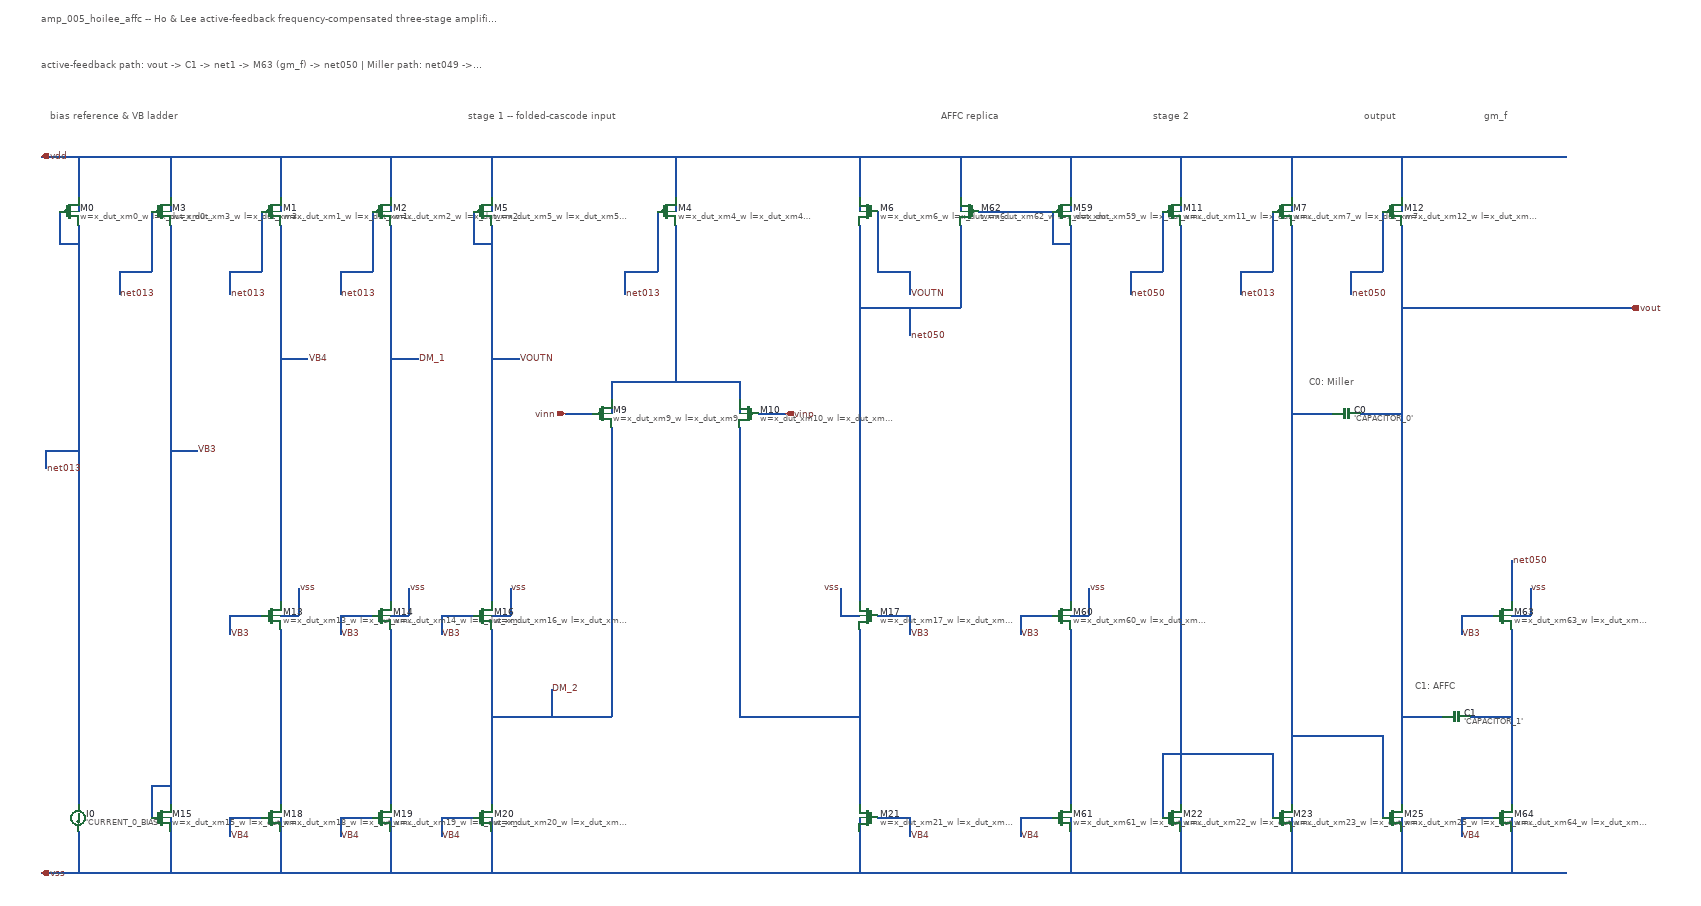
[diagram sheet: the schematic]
v {xschem version=3.4.6 file_version=1.2
}
G {}
K {}
V {}
S {}
E {}
T {amp_005_hoilee_affc   --   Ho \& Lee active-feedback frequency-compensated three-stage amplifier   (IHP SG13G2)} 140 -2090 0 0 0.6 0.6 {}
T {active-feedback path:   vout  ->  C1  ->  net1  ->  M63 (gm_f)  ->  net050      |     Miller path:   net049  ->  C0  ->  vout} 140 -1990 0 0 0.42 0.42 {}
T {bias reference \& VB ladder} 160 -1880 0 0 0.45 0.45 {}
T {stage 1  --  folded-cascode input} 1070 -1880 0 0 0.45 0.45 {}
T {AFFC replica} 2100 -1880 0 0 0.45 0.45 {}
T {stage 2} 2560 -1880 0 0 0.45 0.45 {}
T {output} 3020 -1880 0 0 0.45 0.45 {}
T {gm_f} 3280 -1880 0 0 0.45 0.45 {}
T {C0: Miller} 2900 -1300 0 0 0.4 0.4 {}
T {C1: AFFC} 3130 -640 0 0 0.4 0.4 {}
N 140 -1780 3460 -1780 {}
N 140 -220 3460 -220 {}
N 220 -1780 220 -1660 {}
N 420 -1780 420 -1660 {}
N 660 -1780 660 -1660 {}
N 900 -1780 900 -1660 {}
N 420 -340 420 -220 {}
N 660 -340 660 -220 {}
N 900 -340 900 -220 {}
N 1120 -1780 1120 -1660 {}
N 1120 -340 1120 -220 {}
N 1520 -1780 1520 -1660 {}
N 1920 -1780 1920 -1660 {}
N 1920 -340 1920 -220 {}
N 2140 -1780 2140 -1660 {}
N 2380 -1780 2380 -1660 {}
N 2380 -340 2380 -220 {}
N 2620 -1780 2620 -1660 {}
N 2620 -340 2620 -220 {}
N 2860 -1780 2860 -1660 {}
N 2860 -340 2860 -220 {}
N 3100 -1780 3100 -1660 {}
N 3100 -340 3100 -220 {}
N 3340 -340 3340 -220 {}
N 220 -310 220 -220 {}
N 180 -1660 180 -1590 {}
N 180 -1590 220 -1590 {}
N 220 -1630 220 -370 {}
N 150 -1140 220 -1140 {}
N 150 -1140 150 -1100 {}
N 380 -1660 380 -1530 {}
N 380 -1530 310 -1530 {}
N 310 -1530 310 -1480 {}
N 620 -1660 620 -1530 {}
N 620 -1530 550 -1530 {}
N 550 -1530 550 -1480 {}
N 860 -1660 860 -1530 {}
N 860 -1530 790 -1530 {}
N 790 -1530 790 -1480 {}
N 1480 -1660 1480 -1530 {}
N 1480 -1530 1410 -1530 {}
N 1410 -1530 1410 -1480 {}
N 2820 -1660 2820 -1530 {}
N 2820 -1530 2750 -1530 {}
N 2750 -1530 2750 -1480 {}
N 420 -1630 420 -370 {}
N 380 -340 380 -410 {}
N 380 -410 420 -410 {}
N 420 -1140 480 -1140 {}
N 620 -780 550 -780 {}
N 550 -780 550 -740 {}
N 860 -780 790 -780 {}
N 790 -780 790 -740 {}
N 1080 -780 1010 -780 {}
N 1010 -780 1010 -740 {}
N 1960 -780 2030 -780 {}
N 2030 -780 2030 -740 {}
N 2340 -780 2270 -780 {}
N 2270 -780 2270 -740 {}
N 3300 -780 3230 -780 {}
N 3230 -780 3230 -740 {}
N 660 -1630 660 -810 {}
N 660 -1340 720 -1340 {}
N 620 -340 550 -340 {}
N 550 -340 550 -300 {}
N 860 -340 790 -340 {}
N 790 -340 790 -300 {}
N 1080 -340 1010 -340 {}
N 1010 -340 1010 -300 {}
N 1960 -340 2030 -340 {}
N 2030 -340 2030 -300 {}
N 2340 -340 2270 -340 {}
N 2270 -340 2270 -300 {}
N 3300 -340 3230 -340 {}
N 3230 -340 3230 -300 {}
N 660 -750 660 -370 {}
N 900 -1630 900 -810 {}
N 900 -1340 960 -1340 {}
N 900 -750 900 -370 {}
N 660 -780 700 -780 {}
N 700 -780 700 -840 {}
N 900 -780 940 -780 {}
N 940 -780 940 -840 {}
N 1120 -1630 1120 -810 {}
N 1080 -1660 1080 -1590 {}
N 1080 -1590 1120 -1590 {}
N 1120 -1340 1180 -1340 {}
N 1960 -1660 1960 -1530 {}
N 1960 -1530 2030 -1530 {}
N 2030 -1530 2030 -1480 {}
N 1120 -780 1160 -780 {}
N 1160 -780 1160 -840 {}
N 1520 -1630 1520 -1290 {}
N 1380 -1290 1660 -1290 {}
N 1380 -1290 1380 -1220 {}
N 1660 -1290 1660 -1220 {}
N 1280 -1220 1340 -1220 {}
N 1700 -1220 1760 -1220 {}
N 1380 -1190 1380 -560 {}
N 1120 -560 1380 -560 {}
N 1120 -750 1120 -370 {}
N 1250 -560 1250 -620 {}
N 1660 -1190 1660 -560 {}
N 1660 -560 1920 -560 {}
N 1920 -750 1920 -370 {}
N 1920 -780 1880 -780 {}
N 1880 -780 1880 -840 {}
N 1920 -1630 1920 -810 {}
N 1920 -1450 2140 -1450 {}
N 2140 -1630 2140 -1450 {}
N 2030 -1450 2030 -1390 {}
N 2580 -1660 2580 -1530 {}
N 2580 -1530 2510 -1530 {}
N 2510 -1530 2510 -1480 {}
N 3060 -1660 3060 -1530 {}
N 3060 -1530 2990 -1530 {}
N 2990 -1530 2990 -1480 {}
N 3340 -810 3340 -900 {}
N 2380 -1630 2380 -810 {}
N 2340 -1660 2340 -1590 {}
N 2340 -1590 2380 -1590 {}
N 2180 -1660 2340 -1660 {}
N 2380 -750 2380 -370 {}
N 2380 -780 2420 -780 {}
N 2420 -780 2420 -840 {}
N 2620 -1630 2620 -370 {}
N 2580 -340 2580 -480 {}
N 2580 -480 2620 -480 {}
N 2820 -340 2820 -480 {}
N 2620 -480 2820 -480 {}
N 2860 -1630 2860 -370 {}
N 3060 -340 3060 -520 {}
N 2860 -520 3060 -520 {}
N 2860 -1220 2950 -1220 {}
N 3100 -1630 3100 -370 {}
N 3010 -1220 3100 -1220 {}
N 3100 -560 3190 -560 {}
N 3100 -1450 3600 -1450 {}
N 3250 -560 3340 -560 {}
N 3340 -750 3340 -370 {}
N 3340 -780 3380 -780 {}
N 3380 -780 3380 -840 {}
C {devices/sg13_lv_pmos_np.sym} 200 -1660 0 0 {name=M0 model=sg13_lv_pmos spiceprefix=X w=x_dut_xm0_w l=x_dut_xm0_l m=x_dut_xm0_m}
C {devices/sg13_lv_pmos_np.sym} 400 -1660 0 0 {name=M3 model=sg13_lv_pmos spiceprefix=X w=x_dut_xm3_w l=x_dut_xm3_l m=x_dut_xm3_m}
C {devices/sg13_lv_pmos_np.sym} 640 -1660 0 0 {name=M1 model=sg13_lv_pmos spiceprefix=X w=x_dut_xm1_w l=x_dut_xm1_l m=x_dut_xm1_m}
C {devices/sg13_lv_pmos_np.sym} 880 -1660 0 0 {name=M2 model=sg13_lv_pmos spiceprefix=X w=x_dut_xm2_w l=x_dut_xm2_l m=x_dut_xm2_m}
C {devices/sg13_lv_nmos_np.sym} 400 -340 0 0 {name=M15 model=sg13_lv_nmos spiceprefix=X w=x_dut_xm15_w l=x_dut_xm15_l m=x_dut_xm15_m}
C {devices/sg13_lv_nmos_np.sym} 640 -780 0 0 {name=M13 model=sg13_lv_nmos spiceprefix=X w=x_dut_xm13_w l=x_dut_xm13_l m=x_dut_xm13_m}
C {devices/sg13_lv_nmos_np.sym} 640 -340 0 0 {name=M18 model=sg13_lv_nmos spiceprefix=X w=x_dut_xm18_w l=x_dut_xm18_l m=x_dut_xm18_m}
C {devices/sg13_lv_nmos_np.sym} 880 -780 0 0 {name=M14 model=sg13_lv_nmos spiceprefix=X w=x_dut_xm14_w l=x_dut_xm14_l m=x_dut_xm14_m}
C {devices/sg13_lv_nmos_np.sym} 880 -340 0 0 {name=M19 model=sg13_lv_nmos spiceprefix=X w=x_dut_xm19_w l=x_dut_xm19_l m=x_dut_xm19_m}
C {devices/sg13_lv_pmos_np.sym} 1100 -1660 0 0 {name=M5 model=sg13_lv_pmos spiceprefix=X w=x_dut_xm5_w l=x_dut_xm5_l m=x_dut_xm5_m}
C {devices/sg13_lv_nmos_np.sym} 1100 -780 0 0 {name=M16 model=sg13_lv_nmos spiceprefix=X w=x_dut_xm16_w l=x_dut_xm16_l m=x_dut_xm16_m}
C {devices/sg13_lv_nmos_np.sym} 1100 -340 0 0 {name=M20 model=sg13_lv_nmos spiceprefix=X w=x_dut_xm20_w l=x_dut_xm20_l m=x_dut_xm20_m}
C {devices/sg13_lv_pmos_np.sym} 1360 -1220 0 0 {name=M9 model=sg13_lv_pmos spiceprefix=X w=x_dut_xm9_w l=x_dut_xm9_l m=x_dut_xm9_m}
C {devices/sg13_lv_pmos_np.sym} 1500 -1660 0 0 {name=M4 model=sg13_lv_pmos spiceprefix=X w=x_dut_xm4_w l=x_dut_xm4_l m=x_dut_xm4_m}
C {devices/sg13_lv_pmos_np.sym} 1680 -1220 0 1 {name=M10 model=sg13_lv_pmos spiceprefix=X w=x_dut_xm10_w l=x_dut_xm10_l m=x_dut_xm10_m}
C {devices/sg13_lv_pmos_np.sym} 1940 -1660 0 1 {name=M6 model=sg13_lv_pmos spiceprefix=X w=x_dut_xm6_w l=x_dut_xm6_l m=x_dut_xm6_m}
C {devices/sg13_lv_nmos_np.sym} 1940 -780 0 1 {name=M17 model=sg13_lv_nmos spiceprefix=X w=x_dut_xm17_w l=x_dut_xm17_l m=x_dut_xm17_m}
C {devices/sg13_lv_nmos_np.sym} 1940 -340 0 1 {name=M21 model=sg13_lv_nmos spiceprefix=X w=x_dut_xm21_w l=x_dut_xm21_l m=x_dut_xm21_m}
C {devices/sg13_lv_pmos_np.sym} 2160 -1660 0 1 {name=M62 model=sg13_lv_pmos spiceprefix=X w=x_dut_xm62_w l=x_dut_xm62_l m=x_dut_xm62_m}
C {devices/sg13_lv_pmos_np.sym} 2360 -1660 0 0 {name=M59 model=sg13_lv_pmos spiceprefix=X w=x_dut_xm59_w l=x_dut_xm59_l m=x_dut_xm59_m}
C {devices/sg13_lv_nmos_np.sym} 2360 -780 0 0 {name=M60 model=sg13_lv_nmos spiceprefix=X w=x_dut_xm60_w l=x_dut_xm60_l m=x_dut_xm60_m}
C {devices/sg13_lv_nmos_np.sym} 2360 -340 0 0 {name=M61 model=sg13_lv_nmos spiceprefix=X w=x_dut_xm61_w l=x_dut_xm61_l m=x_dut_xm61_m}
C {devices/sg13_lv_pmos_np.sym} 2600 -1660 0 0 {name=M11 model=sg13_lv_pmos spiceprefix=X w=x_dut_xm11_w l=x_dut_xm11_l m=x_dut_xm11_m}
C {devices/sg13_lv_nmos_np.sym} 2600 -340 0 0 {name=M22 model=sg13_lv_nmos spiceprefix=X w=x_dut_xm22_w l=x_dut_xm22_l m=x_dut_xm22_m}
C {devices/sg13_lv_pmos_np.sym} 2840 -1660 0 0 {name=M7 model=sg13_lv_pmos spiceprefix=X w=x_dut_xm7_w l=x_dut_xm7_l m=x_dut_xm7_m}
C {devices/sg13_lv_nmos_np.sym} 2840 -340 0 0 {name=M23 model=sg13_lv_nmos spiceprefix=X w=x_dut_xm23_w l=x_dut_xm23_l m=x_dut_xm23_m}
C {devices/sg13_lv_pmos_np.sym} 3080 -1660 0 0 {name=M12 model=sg13_lv_pmos spiceprefix=X w=x_dut_xm12_w l=x_dut_xm12_l m=x_dut_xm12_m}
C {devices/sg13_lv_nmos_np.sym} 3080 -340 0 0 {name=M25 model=sg13_lv_nmos spiceprefix=X w=x_dut_xm25_w l=x_dut_xm25_l m=x_dut_xm25_m}
C {devices/sg13_lv_nmos_np.sym} 3320 -780 0 0 {name=M63 model=sg13_lv_nmos spiceprefix=X w=x_dut_xm63_w l=x_dut_xm63_l m=x_dut_xm63_m}
C {devices/sg13_lv_nmos_np.sym} 3320 -340 0 0 {name=M64 model=sg13_lv_nmos spiceprefix=X w=x_dut_xm64_w l=x_dut_xm64_l m=x_dut_xm64_m}
C {devices/isource_np.sym} 220 -340 0 0 {name=I0 value='CURRENT_0_BIAS'}
C {devices/capa_np.sym} 2980 -1220 3 0 {name=C0 value='CAPACITOR_0'}
C {devices/capa_np.sym} 3220 -560 3 0 {name=C1 value='CAPACITOR_1'}
C {devices/iopin.sym} 140 -1780 0 1 {name=p0 lab=vdd}
C {devices/iopin.sym} 140 -220 0 1 {name=p1 lab=vss}
C {devices/lab_pin.sym} 150 -1100 0 1 {name=l2 sig_type=std_logic lab=net013}
C {devices/lab_pin.sym} 310 -1480 0 1 {name=l3 sig_type=std_logic lab=net013}
C {devices/lab_pin.sym} 550 -1480 0 1 {name=l4 sig_type=std_logic lab=net013}
C {devices/lab_pin.sym} 790 -1480 0 1 {name=l5 sig_type=std_logic lab=net013}
C {devices/lab_pin.sym} 1410 -1480 0 1 {name=l6 sig_type=std_logic lab=net013}
C {devices/lab_pin.sym} 2750 -1480 0 1 {name=l7 sig_type=std_logic lab=net013}
C {devices/lab_pin.sym} 480 -1140 0 1 {name=l8 sig_type=std_logic lab=VB3}
C {devices/lab_pin.sym} 550 -740 0 1 {name=l9 sig_type=std_logic lab=VB3}
C {devices/lab_pin.sym} 790 -740 0 1 {name=l10 sig_type=std_logic lab=VB3}
C {devices/lab_pin.sym} 1010 -740 0 1 {name=l11 sig_type=std_logic lab=VB3}
C {devices/lab_pin.sym} 2030 -740 0 1 {name=l12 sig_type=std_logic lab=VB3}
C {devices/lab_pin.sym} 2270 -740 0 1 {name=l13 sig_type=std_logic lab=VB3}
C {devices/lab_pin.sym} 3230 -740 0 1 {name=l14 sig_type=std_logic lab=VB3}
C {devices/lab_pin.sym} 720 -1340 0 1 {name=l15 sig_type=std_logic lab=VB4}
C {devices/lab_pin.sym} 550 -300 0 1 {name=l16 sig_type=std_logic lab=VB4}
C {devices/lab_pin.sym} 790 -300 0 1 {name=l17 sig_type=std_logic lab=VB4}
C {devices/lab_pin.sym} 1010 -300 0 1 {name=l18 sig_type=std_logic lab=VB4}
C {devices/lab_pin.sym} 2030 -300 0 1 {name=l19 sig_type=std_logic lab=VB4}
C {devices/lab_pin.sym} 2270 -300 0 1 {name=l20 sig_type=std_logic lab=VB4}
C {devices/lab_pin.sym} 3230 -300 0 1 {name=l21 sig_type=std_logic lab=VB4}
C {devices/lab_pin.sym} 960 -1340 0 1 {name=l22 sig_type=std_logic lab=DM_1}
C {devices/lab_pin.sym} 700 -840 0 1 {name=l23 sig_type=std_logic lab=vss}
C {devices/lab_pin.sym} 940 -840 0 1 {name=l24 sig_type=std_logic lab=vss}
C {devices/lab_pin.sym} 1180 -1340 0 1 {name=l25 sig_type=std_logic lab=VOUTN}
C {devices/lab_pin.sym} 2030 -1480 0 1 {name=l26 sig_type=std_logic lab=VOUTN}
C {devices/lab_pin.sym} 1160 -840 0 1 {name=l27 sig_type=std_logic lab=vss}
C {devices/ipin.sym} 1280 -1220 0 0 {name=p28 lab=vinn}
C {devices/ipin.sym} 1760 -1220 0 1 {name=p29 lab=vinp}
C {devices/lab_pin.sym} 1250 -620 0 1 {name=l30 sig_type=std_logic lab=DM_2}
C {devices/lab_pin.sym} 1880 -840 0 0 {name=l31 sig_type=std_logic lab=vss}
C {devices/lab_pin.sym} 2030 -1390 0 1 {name=l32 sig_type=std_logic lab=net050}
C {devices/lab_pin.sym} 2510 -1480 0 1 {name=l33 sig_type=std_logic lab=net050}
C {devices/lab_pin.sym} 2990 -1480 0 1 {name=l34 sig_type=std_logic lab=net050}
C {devices/lab_pin.sym} 3340 -900 0 1 {name=l35 sig_type=std_logic lab=net050}
C {devices/lab_pin.sym} 2420 -840 0 1 {name=l36 sig_type=std_logic lab=vss}
C {devices/opin.sym} 3600 -1450 0 0 {name=p37 lab=vout}
C {devices/lab_pin.sym} 3380 -840 0 1 {name=l38 sig_type=std_logic lab=vss}
